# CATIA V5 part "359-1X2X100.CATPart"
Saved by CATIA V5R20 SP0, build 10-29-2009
Part number: 359-1X2X100
Definition: NONE
Nomenclature: 359-1X2X100
Source: Unknown
Description: 359-1X2X100
Bounding box of the stored display mesh (mm): x -2 to 98, y -2 to 2, z -2 to 2
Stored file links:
  C:\Users\Utente\Desktop\IO LAVORO\3D X SITO CF\X SITO\PLASTICA\359\359-1X2X100.CATPart

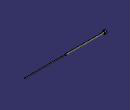
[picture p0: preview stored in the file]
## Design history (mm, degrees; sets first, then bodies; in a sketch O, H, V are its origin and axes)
Body1 "359-1X2X100" (main body)
  Solid1: solid without history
